One B-rep face of a CAD part: STEP entity #67.
In plain terms, the planar face has unit normal (1, 0, 0).
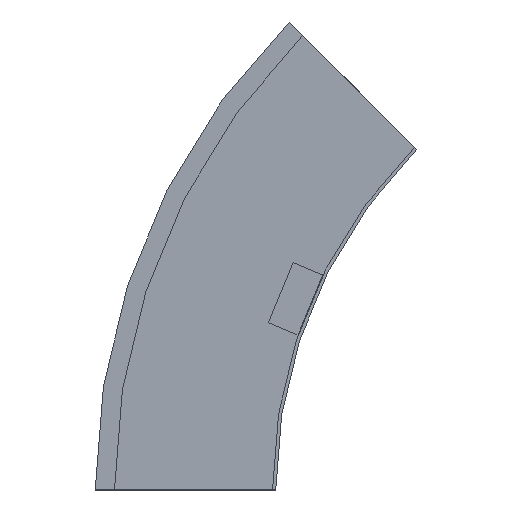
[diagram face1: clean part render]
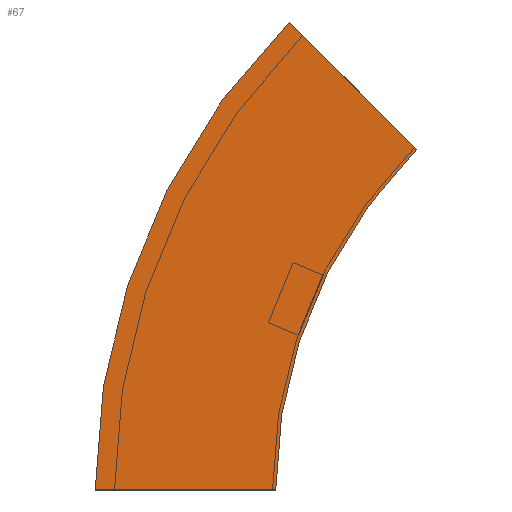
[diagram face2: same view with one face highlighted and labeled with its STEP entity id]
Its self-contained STEP definition (entity closure, numbers rounded to 3 decimals):
#1 = EDGE_LOOP ( 'NONE', ( #279, #19, #52, #278 ) ) ;
#19 = ORIENTED_EDGE ( 'NONE', *, *, #290, .F. ) ;
#33 = CIRCLE ( 'NONE', #100, 412.5 ) ;
#37 = DIRECTION ( 'NONE',  ( 0., 1., 0. ) ) ;
#52 = ORIENTED_EDGE ( 'NONE', *, *, #449, .F. ) ;
#67 = ADVANCED_FACE ( 'NONE', ( #166 ), #454, .T. ) ;
#72 = DIRECTION ( 'NONE',  ( 0., 1., 0. ) ) ;
#92 = AXIS2_PLACEMENT_3D ( 'NONE', #289, #494, #510 ) ;
#100 = AXIS2_PLACEMENT_3D ( 'NONE', #121, #288, #72 ) ;
#110 = VERTEX_POINT ( 'NONE', #375 ) ;
#111 = VERTEX_POINT ( 'NONE', #335 ) ;
#121 = CARTESIAN_POINT ( 'NONE',  ( 0., -300., 0. ) ) ;
#166 = FACE_OUTER_BOUND ( 'NONE', #1, .T. ) ;
#174 = LINE ( 'NONE', #424, #550 ) ;
#184 = EDGE_CURVE ( 'NONE', #469, #110, #174, .T. ) ;
#272 = EDGE_CURVE ( 'NONE', #110, #496, #33, .T. ) ;
#275 = CIRCLE ( 'NONE', #440, 300. ) ;
#278 = ORIENTED_EDGE ( 'NONE', *, *, #184, .T. ) ;
#279 = ORIENTED_EDGE ( 'NONE', *, *, #272, .T. ) ;
#288 = DIRECTION ( 'NONE',  ( 1., 0., 0. ) ) ;
#289 = CARTESIAN_POINT ( 'NONE',  ( 0., 0., 0. ) ) ;
#290 = EDGE_CURVE ( 'NONE', #111, #496, #339, .T. ) ;
#335 = CARTESIAN_POINT ( 'NONE',  ( 0., -87.868, 212.132 ) ) ;
#339 = LINE ( 'NONE', #558, #446 ) ;
#351 = CARTESIAN_POINT ( 'NONE',  ( 0., -8.318, 291.682 ) ) ;
#375 = CARTESIAN_POINT ( 'NONE',  ( 0., 112.5, 0. ) ) ;
#420 = CARTESIAN_POINT ( 'NONE',  ( 0., -300., 0. ) ) ;
#424 = CARTESIAN_POINT ( 'NONE',  ( 0., 0., 0. ) ) ;
#427 = DIRECTION ( 'NONE',  ( 0., 0.707, 0.707 ) ) ;
#440 = AXIS2_PLACEMENT_3D ( 'NONE', #420, #514, #37 ) ;
#446 = VECTOR ( 'NONE', #427, 1000. ) ;
#449 = EDGE_CURVE ( 'NONE', #469, #111, #275, .T. ) ;
#454 = PLANE ( 'NONE',  #92 ) ;
#466 = CARTESIAN_POINT ( 'NONE',  ( 0., 0., 0. ) ) ;
#469 = VERTEX_POINT ( 'NONE', #466 ) ;
#494 = DIRECTION ( 'NONE',  ( 1., 0., 0. ) ) ;
#496 = VERTEX_POINT ( 'NONE', #351 ) ;
#505 = DIRECTION ( 'NONE',  ( 0., 1., 0. ) ) ;
#510 = DIRECTION ( 'NONE',  ( 0., 0., -1. ) ) ;
#514 = DIRECTION ( 'NONE',  ( 1., 0., 0. ) ) ;
#550 = VECTOR ( 'NONE', #505, 1000. ) ;
#558 = CARTESIAN_POINT ( 'NONE',  ( 0., -87.868, 212.132 ) ) ;
